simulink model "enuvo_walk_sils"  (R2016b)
settings: Solver=ode23tb  StartTime=0.0  StopTime=LAST_TIME  FixedStep=0.01  EnableMultiTasking=on
PreLoadFcn:
  | load('PID_PARAMETER');
  | N=40;
  | eta=1;
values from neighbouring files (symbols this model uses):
  A = [1 0 0 0 0 0    [symbolic_sample.m]
  s = robot_para.s    [kinematics_calc.m]    (also in plot_graph.m; robot_parameter.m = 40; robot_view.m)
undefined symbols (not defined in the file or in its folder): arm, bridge, constant, deg, kg, m, powergui, pulses, rad, S, Torque
libraries: mblibv1 x53, powerlib x7, powerlib_extras x1
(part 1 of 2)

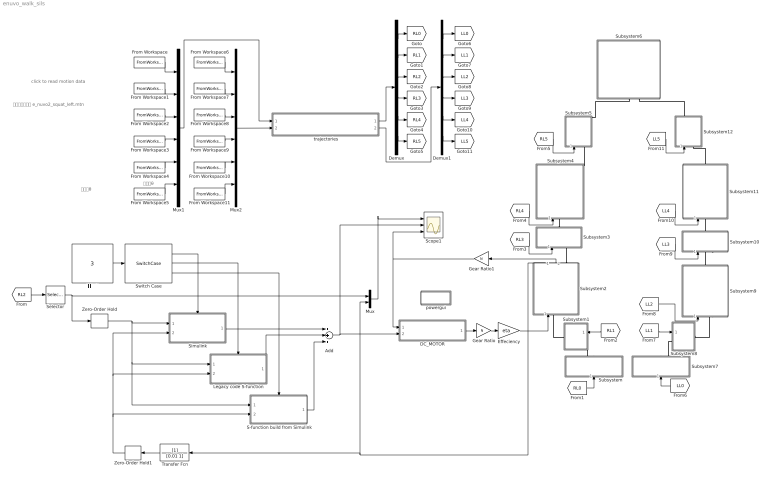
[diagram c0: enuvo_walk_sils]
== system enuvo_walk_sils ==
  note: click to read motion data
  note: 使用モーション e_nuvo2_squat_left.mtn
  note: 右足のθ
  note: 左足のθ
  Add : Sum  Inputs=+++
  DC_MOTOR : Subsystem
  Demux : Demux  Outputs=6
  Demux1 : Demux  Outputs=6
  Effeciency : Gain  Gain=eta
  From Workspace : FromWorkspace  VariableName=ID0_data  SampleTime=0
  From Workspace1 : FromWorkspace  VariableName=ID1_data  SampleTime=0
  From Workspace10 : FromWorkspace  VariableName=ID10_data  SampleTime=0
  From Workspace11 : FromWorkspace  VariableName=ID11_data  SampleTime=0
  From Workspace2 : FromWorkspace  VariableName=ID2_data  SampleTime=0
  From Workspace3 : FromWorkspace  VariableName=ID3_data  SampleTime=0
  From Workspace4 : FromWorkspace  VariableName=ID4_data  SampleTime=0
  From Workspace5 : FromWorkspace  VariableName=ID5_data  SampleTime=0
  From Workspace6 : FromWorkspace  VariableName=ID6_data  SampleTime=0
  From Workspace7 : FromWorkspace  VariableName=ID7_data  SampleTime=0
  From Workspace8 : FromWorkspace  VariableName=ID8_data  SampleTime=0
  From Workspace9 : FromWorkspace  VariableName=ID9_data  SampleTime=0
  Gear Ratio : Gain  Gain=N
  Gear Ratio1 : Gain  Gain=N
  Legacy code S-function : Subsystem  TreatAsAtomicUnit=on
  Mux : Mux  Inputs=2
  Mux1 : Mux  Inputs=6
  Mux2 : Mux  Inputs=6
  S-function build from Simulink : Subsystem  TreatAsAtomicUnit=on
  Scope1 : Scope  NumInputPorts=3
  Selector : Selector  InputPortWidth=3  IndexOptions=Index vector (dialog)  Indices=[1]  OutputSizes=1
  Simulink : Subsystem  TreatAsAtomicUnit=on
  Subsystem : Subsystem
  Subsystem1 : Subsystem
  Subsystem10 : Subsystem
  Subsystem11 : Subsystem
  Subsystem12 : Subsystem
  Subsystem2 : Subsystem
  Subsystem3 : Subsystem
  Subsystem4 : Subsystem
  Subsystem5 : Subsystem
  Subsystem6 : Subsystem
  Subsystem7 : Subsystem
  Subsystem8 : Subsystem
  Subsystem9 : Subsystem
  Switch Case : SwitchCase  CaseConditions={1,2,3}  ShowDefaultCase=off  SampleTime=20e-3
  Transfer Fcn : TransferFcn  Denominator=[0.01 1]
  Zero-Order Hold : ZeroOrderHold  SampleTime=20e-3
  Zero-Order Hold1 : ZeroOrderHold  SampleTime=20e-3
  powergui : Subsystem  AncestorBlock=powerlib/powergui  InitFcn=powergui( 'InitFcn_Callback' , gcb , 0 , [ ] );
  trajectories : Subsystem
  制御器切替 : Constant  Value=3
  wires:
  Gear Ratio/1 -> Effeciency/1
  DC_MOTOR/1(Te (n m)) -> Gear Ratio/1
  Selector/1 -> Mux/1, Zero-Order Hold/1
  Effeciency/1 -> Subsystem2/1(Torque(N m))
  Subsystem2/1(Theta(deg)) -> Mux/2, Transfer Fcn/1
  Mux/1 -> Scope1/1
  [RL2] -> Selector/1
  Subsystem2/2(w(rad/s)) -> Gear Ratio1/1
  Zero-Order Hold/1 -> Simulink/1(In1), Legacy code S-function/1(In1), S-function build from Simulink/1(In1)
  Zero-Order Hold1/1 -> Simulink/2(In2), Legacy code S-function/2(In2), S-function build from Simulink/2(In2)
  From Workspace/1 -> Mux1/1
  From Workspace1/1 -> Mux1/2
  From Workspace2/1 -> Mux1/3
  From Workspace3/1 -> Mux1/4
  From Workspace4/1 -> Mux1/5
  From Workspace5/1 -> Mux1/6
  From Workspace6/1 -> Mux2/1
  From Workspace7/1 -> Mux2/2
  From Workspace8/1 -> Mux2/3
  From Workspace9/1 -> Mux2/4
  From Workspace10/1 -> Mux2/5
  From Workspace11/1 -> Mux2/6
  Mux1/1 -> trajectories/1(θof RIGHT LEGS)
  Mux2/1 -> trajectories/2(θof LEFT LEGS)
  trajectories/1(θ,θ',θ''of RIGHT LEGS) -> Demux/1
  trajectories/2(θ,θ',θ''of LEFT LEGS) -> Demux1/1
  Demux/1 -> [RL0]
  Demux/2 -> [RL1]
  Demux/3 -> [RL2]
  Demux/4 -> [RL3]
  Demux/5 -> [RL4]
  Demux/6 -> [RL5]
  Demux1/1 -> [LL0]
  Demux1/2 -> [LL1]
  Demux1/3 -> [LL2]
  Demux1/4 -> [LL3]
  Demux1/5 -> [LL4]
  Demux1/6 -> [LL5]
  [RL0] -> Subsystem/1(motion)
  [RL1] -> Subsystem1/1(motion)
  [RL3] -> Subsystem3/1(motion)
  [RL4] -> Subsystem4/1(motion)
  [RL5] -> Subsystem5/1(motion)
  [LL0] -> Subsystem7/1(motion)
  [LL1] -> Subsystem8/1(motion)
  [LL2] -> Subsystem9/1(motion)
  [LL3] -> Subsystem10/1(motion)
  [LL4] -> Subsystem11/1(motion)
  [LL5] -> Subsystem12/1(motion)
  制御器切替/1 -> Switch Case/1
  Switch Case/1 -> Simulink/Action
  Switch Case/2 -> Legacy code S-function/Action
  Legacy code S-function/1(Out1) -> Add/2
  Switch Case/3 -> S-function build from Simulink/Action
  Simulink/1(Out1) -> Add/1
  S-function build from Simulink/1(Out1) -> Add/3
  Add/1 -> DC_MOTOR/2(Duty ratio[-]), Scope1/2
  Transfer Fcn/1 -> Zero-Order Hold1/1
  Gear Ratio1/1 -> DC_MOTOR/1(N w[rad/s]), Scope1/3
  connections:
  Subsystem1/LConn1 -- Subsystem/RConn1
  Subsystem2/LConn1 -- Subsystem1/RConn1
  Subsystem3/LConn1 -- Subsystem2/RConn1
  Subsystem6/LConn1 -- Subsystem5/RConn1
  Subsystem10/RConn1 -- Subsystem11/LConn1
  Subsystem9/RConn1 -- Subsystem10/LConn1
  Subsystem8/RConn1 -- Subsystem9/LConn1
  Subsystem8/LConn1 -- Subsystem7/RConn1
  Subsystem3/RConn1 -- Subsystem4/LConn1
  Subsystem4/RConn1 -- Subsystem5/LConn1
  Subsystem6/LConn2 -- Subsystem12/RConn1
  Subsystem12/LConn1 -- Subsystem11/RConn1

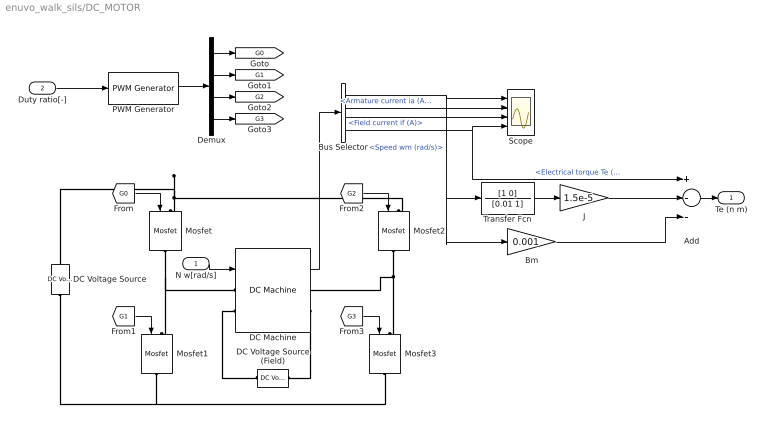
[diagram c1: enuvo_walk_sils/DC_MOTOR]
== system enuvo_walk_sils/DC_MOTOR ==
  N w[rad/s] : Inport
  Duty ratio[-] : Inport  Port=2
  Add : Sum  Inputs=+--
  Bm : Gain  Gain=0.001
  Bus Selector : BusSelector  OutputSignals=Speed wm (rad/s),Armature current ia (A),Field current if (A),Electrical torque Te (n m)
  DC Machine : powerlib/Machines/DC Machine  PresetModel=No  MechanicalLoad=Speed w  FieldType=Wound  ShowDetailedParameters=on  MeasurementBus=off  RLa="[ 10  4.4e-3]"  RLf="[ 24  0 ]"  Laf=0.05  MachineConstant=Torque constant (N.m/A)  Ke=1.8  Kt=1.8  J=1.5e-5  Bm=0.001  Tf=0  w0=0  Ifinit=1  TsPowergui=0  TsBlock=-1
  DC Voltage Source : powerlib/Electrical Sources/DC Voltage Source  Amplitude=24  Measurements=None
  DC Voltage Source (Field) : powerlib/Electrical Sources/DC Voltage Source  Amplitude=24  Measurements=None
  Demux : Demux
  J : Gain  Gain=1.5e-5
  Mosfet{,1..3} (4 alike) : powerlib/Power Electronics/Mosfet  Ron=0.3  Lon=0  Rd=0.01  Vfd=0  IC=0  Rs=5e9  Cs=inf  Measurements=off
  PWM Generator : powerlib_extras/Control  Blocks/PWM Generator  GeneratorMode="2-arm  bridge (4 pulses)"  Fc=500  Internal=off  mIndex=0.4  Freq=60  Phase=0
  Scope : Scope  NumInputPorts=4
  Transfer Fcn : TransferFcn  Numerator=[1 0]  Denominator=[0.01 1]
  Te (n m) : Outport
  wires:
  Duty ratio[-]/1 -> PWM Generator/1
  PWM Generator/1 -> Demux/1
  [G2] -> Mosfet2/1
  [G1] -> Mosfet1/1
  [G0] -> Mosfet/1
  Demux/4 -> [G3]
  Demux/3 -> [G2]
  Demux/2 -> [G1]
  Demux/1 -> [G0]
  Bus Selector/1 -> Scope/1, Bm/1, Transfer Fcn/1  "<Speed wm (rad/s)>"
  Bus Selector/2 -> Scope/2  "<Armature current ia (A)>"
  [G3] -> Mosfet3/1
  N w[rad/s]/1 -> DC Machine/1
  DC Machine/1 -> Bus Selector/1
  Bus Selector/3 -> Scope/3  "<Field current if (A)>"
  Bus Selector/4 -> Scope/4, Add/1  "<Electrical torque Te (n m)>"
  Bm/1 -> Add/3
  Transfer Fcn/1 -> J/1
  Add/1 -> Te (n m)/1
  J/1 -> Add/2
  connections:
  Mosfet2/RConn1 -- Mosfet3/LConn1 -- DC Machine/RConn1
  Mosfet/RConn1 -- Mosfet1/LConn1 -- DC Machine/LConn1
  Mosfet/LConn1 -- Mosfet2/LConn1 -- DC Voltage Source/RConn1
  Mosfet1/RConn1 -- Mosfet3/RConn1 -- DC Voltage Source/LConn1
  DC Voltage Source (Field)/RConn1 -- DC Machine/LConn2
  DC Machine/RConn2 -- DC Voltage Source (Field)/LConn1

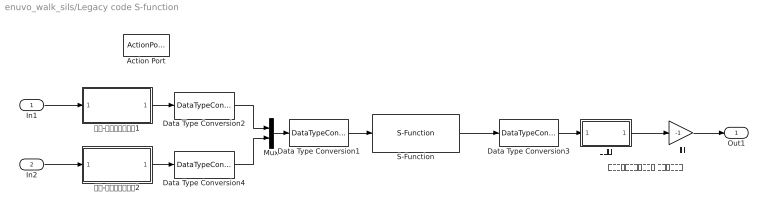
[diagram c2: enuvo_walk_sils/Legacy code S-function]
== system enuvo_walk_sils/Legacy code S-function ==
  note: レガシーコードの仕様と 合わせるため
  In1 : Inport
  In2 : Inport  Port=2
  Action Port : ActionPort  ActionType=case
  Data Type Conversion1 : DataTypeConversion  OutDataTypeStr=double
  Data Type Conversion2 : DataTypeConversion  OutDataTypeStr=uint16
  Data Type Conversion3 : DataTypeConversion  OutDataTypeStr=int16
  Data Type Conversion4 : DataTypeConversion  OutDataTypeStr=uint16
  Mux : Mux  Inputs=2
  S-Function : S-Function  FunctionName=sfun_pid  SFunctionDeploymentMode=off  EnableBusSupport=off
  正規化 : Subsystem
  符号反転 : Gain  Gain=-1
  角度-カウント値変換1 : Subsystem
  角度-カウント値変換2 : Subsystem
  Out1 : Outport
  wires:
  In2/1 -> 角度-カウント値変換2/1(theta[deg])
  符号反転/1 -> Out1/1
  Data Type Conversion4/1 -> Mux/2
  Data Type Conversion2/1 -> Mux/1
  角度-カウント値変換1/1(count[-]) -> Data Type Conversion2/1
  角度-カウント値変換2/1(count[-]) -> Data Type Conversion4/1
  S-Function/1 -> Data Type Conversion3/1
  正規化/1(Out1) -> 符号反転/1
  In1/1 -> 角度-カウント値変換1/1(theta[deg])
  Mux/1 -> Data Type Conversion1/1
  Data Type Conversion1/1 -> S-Function/1
  Data Type Conversion3/1 -> 正規化/1(In1)

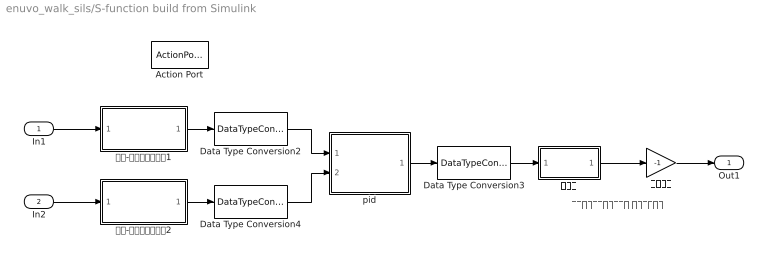
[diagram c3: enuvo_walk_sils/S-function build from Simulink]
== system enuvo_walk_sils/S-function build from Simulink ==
  note: レガシーコードの仕様と 合わせるため
  In1 : Inport
  In2 : Inport  Port=2
  Action Port : ActionPort  ActionType=case
  Data Type Conversion2 : DataTypeConversion  OutDataTypeStr=uint16
  Data Type Conversion3 : DataTypeConversion  OutDataTypeStr=int16
  Data Type Conversion4 : DataTypeConversion  OutDataTypeStr=uint16
  pid : Subsystem
  正規化 : Subsystem
  符号反転 : Gain  Gain=-1
  角度-カウント値変換1 : Subsystem
  角度-カウント値変換2 : Subsystem
  Out1 : Outport
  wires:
  Data Type Conversion3/1 -> 正規化/1(In1)
  In1/1 -> 角度-カウント値変換1/1(theta[deg])
  正規化/1(Out1) -> 符号反転/1
  pid/1(out) -> Data Type Conversion3/1
  角度-カウント値変換2/1(count[-]) -> Data Type Conversion4/1
  角度-カウント値変換1/1(count[-]) -> Data Type Conversion2/1
  符号反転/1 -> Out1/1
  In2/1 -> 角度-カウント値変換2/1(theta[deg])
  Data Type Conversion2/1 -> pid/1(ref)
  Data Type Conversion4/1 -> pid/2(pos)

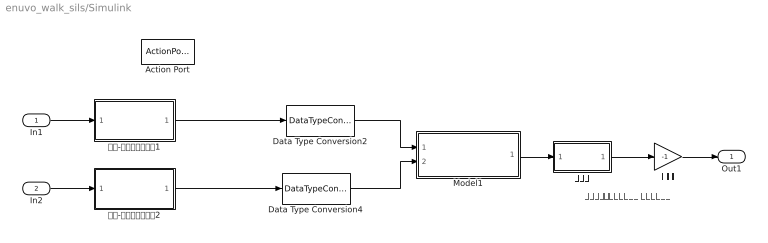
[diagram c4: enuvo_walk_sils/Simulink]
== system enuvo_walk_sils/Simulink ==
  note: レガシーコードの仕様と 合わせるため
  In1 : Inport
  In2 : Inport  Port=2
  Action Port : ActionPort  ActionType=case
  Data Type Conversion2 : DataTypeConversion  OutDataTypeStr=uint16
  Data Type Conversion4 : DataTypeConversion  OutDataTypeStr=uint16
  Model1 : ModelReference  ModelNameDialog=pid_body  ModelReferenceVersion=1.116
  正規化 : Subsystem
  符号反転 : Gain  Gain=-1
  角度-カウント値変換1 : Subsystem
  角度-カウント値変換2 : Subsystem
  Out1 : Outport
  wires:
  In1/1 -> 角度-カウント値変換1/1(theta[deg])
  正規化/1(Out1) -> 符号反転/1
  Model1/1 -> 正規化/1(In1)
  角度-カウント値変換2/1(count[-]) -> Data Type Conversion4/1
  角度-カウント値変換1/1(count[-]) -> Data Type Conversion2/1
  Data Type Conversion2/1 -> Model1/1
  Data Type Conversion4/1 -> Model1/2
  符号反転/1 -> Out1/1
  In2/1 -> 角度-カウント値変換2/1(theta[deg])

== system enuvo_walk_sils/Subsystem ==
  motion : Inport
  Body : mblibv1/Bodies/Body  LConnTagsString=CS1|CS3|CS4|CS5|CS6  RConnTagsString=CS2  UpdateFromCAD=off  DialogClass=MechanicalBodyBlock  Mass=8.7718241e-2  MassUnits=kg  InertiaUnits=kg*m^2  Inertia=1e-3*diag([4.5614162e-2 6.5533040e-2 5.6545514e-2])  Shape=Cylinder  ShapeDims=[1 1]  ShapeUnits=m  ShapeUse=false  Density=1  DensityUnits=kg/m^3  DensityUse=false  GraphicsMode=MACHINE_DEFAULT  BodyColorSelMode=MACHINE_DEFAULT  BodyColor=[1;0;0]  AttachedToCS=CG  CG=Left$CG$[7.96 -5.62 -13.41]$CS1$CS1$mm$[0 0 0]$Euler X-Y-Z$deg$WORLD$false  WorkingFrames=Left$CS1$[0 -20 40]$WORLD$WORLD$mm$[0 0 0]$Euler X-Y-Z$deg$WORLD$true#Right$CS2$[0 0 0]$CS1$CS1$mm$[0 0 0]$Euler X-Y-Z$deg$WORLD$true#Left$CS3$[65 12.5 -40]$CS1$CS1$mm$[0 0 0]$Euler X-Y-Z$deg$WORLD$true#Left$CS4$[-30 12.5 -40]$CS1$CS1$mm$[0 0 0]$Euler X-Y-Z$deg$WORLD$true#Left$CS5$[65 -42.5 -40]$CS1$CS1$mm$[0 0 0]$Euler X-Y-Z$deg$WORLD$true#Left$CS6$[-30 -42.5 -40]$CS1$CS1$mm$[0 0 0]$Euler X-Y-Z$d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  CGPos=[7.96 -5.62 -13.41]  CGRot=[0 0 0]  CS0Pos=[]  CS0Rot=[]  CS1Pos=[0 -20 40]  CS1Rot=[0 0 0]  CS2Pos=[0 0 0]  CS2Rot=[0 0 0]  CS3Pos=[65 12.5 -40]  CS3Rot=[0 0 0]  CS4Pos=[-30 12.5 -40]  CS4Rot=[0 0 0]  CS5Pos=[65 -42.5 -40]  CS5Rot=[0 0 0]  CS6Pos=[-30 -42.5 -40]  CS6Rot=[0 0 0]  CS7Pos=[]  CS7Rot=[]  CS8Pos=[]  CS8Rot=[]  CS9Pos=[]  CS9Rot=[]  CS10Pos=[]  CS10Rot=[]  CS11Pos=[]  CS11Rot=[]  CS12Pos=[]  CS12Rot=[]  CS13Pos=[]  CS13Rot=[]  CS14Pos=[]  CS14Rot=[]  CS15Pos=[]  CS15Rot=[]  CS16Pos=[]  CS16Rot=[]  CS17Pos=[]  CS17Rot=[]  CS18Pos=[]  CS18Rot=[]  CS19Pos=[]  CS19Rot=[]  CS20Pos=[]  CS20Rot=[]
  Joint Actuator : mblibv1/Sensors &  Actuators/Joint Actuator  UpdateFromCAD=off  PhysicalDomain=Mechanical  PortType=blob  ActuationStyle=Motion  AngleUnits=deg  ArcVelocityUnits=deg/s  ArcAccelerationUnits=deg/s^2  CoordPositionUnits=m  VelocityUnits=m/s  AccelerationUnits=m/s^2  ForceUnits=N  TorqueUnits=N-m  ActiveIO=on  Width=3  DialogClass=MechanicalActuatorBlock  Primitive=R1  ReferenceFrame=Absolute (INERTIAL)
  Mechanical Branching Bar : mblibv1/Utilities/Mechanical Branching Bar  LConnTagsString=_newl0  RConnTagsString=SA0|SA1  UpdateFromCAD=off  DialogClass=MechanicalBranchingBarBlock  NumSAPorts=2
  Revolute : mblibv1/Joints/Revolute  LConnTagsString=__newl0|SA1  RConnTagsString=__newr0  UpdateFromCAD=off  NumSAPorts=1  CutJoint=off  MarkAsCut=off  Primitives=revolute  PrimitiveProps=R1$WORLD$[-1 0 0]$revolute  DialogClass=JointBlock  R1Axis=[-1 0 0]
  Conn1 : PMIOPort  Port=1  Side=Right
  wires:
  motion/1 -> Joint Actuator/1
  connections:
  Conn1/RConn1 -- Revolute/RConn1
  Revolute/LConn1 -- Body/RConn1
  Mechanical Branching Bar/LConn1 -- Revolute/LConn2
  Joint Actuator/RConn1 -- Mechanical Branching Bar/RConn1

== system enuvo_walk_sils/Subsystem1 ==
  motion : Inport
  Body1 : mblibv1/Bodies/Body  LConnTagsString=CS1  RConnTagsString=CS2  UpdateFromCAD=off  DialogClass=MechanicalBodyBlock  Mass=1.7789708e-2  MassUnits=kg  InertiaUnits=kg*m^2  Inertia=1e-3*diag([3.2759472e-3 3.3173450e-3 4.8377597e-3])  Shape=Cylinder  ShapeDims=[1 1]  ShapeUnits=m  ShapeUse=false  Density=1  DensityUnits=kg/m^3  DensityUse=false  GraphicsMode=MACHINE_DEFAULT  BodyColorSelMode=MACHINE_DEFAULT  BodyColor=[1;0;0]  AttachedToCS=CG  CG=Left$CG$[-6.4 -13.1 0]$CS1$CS1$mm$[0 0 0]$Euler X-Y-Z$deg$WORLD$false  WorkingFrames=Left$CS1$[0 -20 40]$WORLD$WORLD$mm$[0 0 0]$Euler X-Y-Z$deg$WORLD$true#Right$CS2$[0 0 0]$CS1$CS1$mm$[0 0 0]$Euler X-Y-Z$deg$WORLD$true  CGPos=[-6.4 -13.1 0]  CGRot=[0 0 0]  CS0Pos=[]  CS0Rot=[]  CS1Pos=[0 -20 40]  CS1Rot=[0 0 0]  CS2Pos=[0 0 0]  CS2Rot=[0 0 0]  CS3Pos=[]  CS3Rot=[]  CS4Pos=[]  CS4Rot=[]  CS5Pos=[]  CS5Rot=[]  CS6Pos=[]  CS6Rot=[]  CS7Pos=[]  CS7Rot=[]  CS8Pos=[]  CS8Rot=[]  CS9Pos=[]  CS9Rot=[]  CS10Pos=[]  CS10Rot=[]  CS11Pos=[]  CS11Rot=[]  CS12Pos=[]  CS12Rot=[]  CS13Pos=[]  CS13Rot=[]  CS14Pos=[]  CS14Rot=[]  CS15Pos=[]  CS15Rot=[]  CS16Pos=[]  CS16Rot=[]  CS17Pos=[]  CS17Rot=[]  CS18Pos=[]  CS18Rot=[]  CS19Pos=[]  CS19Rot=[]  CS20Pos=[]  CS20Rot=[]
  Joint Actuator : mblibv1/Sensors &  Actuators/Joint Actuator  UpdateFromCAD=off  PhysicalDomain=Mechanical  PortType=blob  ActuationStyle=Motion  AngleUnits=deg  ArcVelocityUnits=deg/s  ArcAccelerationUnits=deg/s^2  CoordPositionUnits=m  VelocityUnits=m/s  AccelerationUnits=m/s^2  ForceUnits=N  TorqueUnits=N-m  ActiveIO=on  Width=3  DialogClass=MechanicalActuatorBlock  Primitive=R1  ReferenceFrame=Absolute (INERTIAL)
  Mechanical Branching Bar : mblibv1/Utilities/Mechanical Branching Bar  LConnTagsString=_newl0  RConnTagsString=SA0|SA1  UpdateFromCAD=off  DialogClass=MechanicalBranchingBarBlock  NumSAPorts=2
  Revolute1 : mblibv1/Joints/Revolute  LConnTagsString=__newl0|SA1  RConnTagsString=__newr0  UpdateFromCAD=off  NumSAPorts=1  CutJoint=off  MarkAsCut=off  Primitives=revolute  PrimitiveProps=R1$WORLD$[0 1 0]$revolute  DialogClass=JointBlock  R1Axis=[0 1 0]
  Conn1 : PMIOPort  Port=1  Side=Right
  Conn2 : PMIOPort  Port=2  Side=Left
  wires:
  motion/1 -> Joint Actuator/1
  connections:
  Body1/LConn1 -- Conn2/RConn1
  Revolute1/LConn1 -- Body1/RConn1
  Revolute1/RConn1 -- Conn1/RConn1
  Joint Actuator/RConn1 -- Mechanical Branching Bar/RConn1
  Mechanical Branching Bar/LConn1 -- Revolute1/LConn2

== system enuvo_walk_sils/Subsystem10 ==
  motion : Inport
  Body3 : mblibv1/Bodies/Body  LConnTagsString=CS2  RConnTagsString=CS1  UpdateFromCAD=off  DialogClass=MechanicalBodyBlock  Mass=1.9271167e-1  MassUnits=kg  InertiaUnits=kg*m^2  Inertia=1e-3*diag([2.6819268e-1 1.9711091e-1 1.0915260e-1])  Shape=Cylinder  ShapeDims=[1 1]  ShapeUnits=m  ShapeUse=false  Density=1  DensityUnits=kg/m^3  DensityUse=false  GraphicsMode=MACHINE_DEFAULT  BodyColorSelMode=MACHINE_DEFAULT  BodyColor=[1;0;0]  AttachedToCS=CG  CG=Left$CG$[7.6 30.24 -48.36]$CS1$CS1$mm$[0 0 0]$Euler X-Y-Z$deg$WORLD$false  WorkingFrames=Right$CS1$[0 20 210]$WORLD$WORLD$mm$[0 0 0]$Euler X-Y-Z$deg$WORLD$true#Left$CS2$[0 0 -85]$CS1$CS1$mm$[0 0 0]$Euler X-Y-Z$deg$WORLD$true  CGPos=[7.6 30.24 -48.36]  CGRot=[0 0 0]  CS0Pos=[]  CS0Rot=[]  CS1Pos=[0 20 210]  CS1Rot=[0 0 0]  CS2Pos=[0 0 -85]  CS2Rot=[0 0 0]  CS3Pos=[]  CS3Rot=[]  CS4Pos=[]  CS4Rot=[]  CS5Pos=[]  CS5Rot=[]  CS6Pos=[]  CS6Rot=[]  CS7Pos=[]  CS7Rot=[]  CS8Pos=[]  CS8Rot=[]  CS9Pos=[]  CS9Rot=[]  CS10Pos=[]  CS10Rot=[]  CS11Pos=[]  CS11Rot=[]  CS12Pos=[]  CS12Rot=[]  CS13Pos=[]  CS13Rot=[]  CS14Pos=[]  CS14Rot=[]  CS15Pos=[]  CS15Rot=[]  CS16Pos=[]  CS16Rot=[]  CS17Pos=[]  CS17Rot=[]  CS18Pos=[]  CS18Rot=[]  CS19Pos=[]  CS19Rot=[]  CS20Pos=[]  CS20Rot=[]
  Joint Actuator : mblibv1/Sensors &  Actuators/Joint Actuator  UpdateFromCAD=off  PhysicalDomain=Mechanical  PortType=blob  ActuationStyle=Motion  AngleUnits=deg  ArcVelocityUnits=deg/s  ArcAccelerationUnits=deg/s^2  CoordPositionUnits=m  VelocityUnits=m/s  AccelerationUnits=m/s^2  ForceUnits=N  TorqueUnits=N-m  ActiveIO=on  Width=3  DialogClass=MechanicalActuatorBlock  Primitive=R1  ReferenceFrame=Absolute (INERTIAL)
  Mechanical Branching Bar : mblibv1/Utilities/Mechanical Branching Bar  LConnTagsString=_newl0  RConnTagsString=SA0|SA1  UpdateFromCAD=off  DialogClass=MechanicalBranchingBarBlock  NumSAPorts=2
  Revolute3 : mblibv1/Joints/Revolute  LConnTagsString=__newl0|SA1  RConnTagsString=__newr0  UpdateFromCAD=off  NumSAPorts=1  CutJoint=off  MarkAsCut=off  Primitives=revolute  PrimitiveProps=R1$WORLD$[0 -1 0]$revolute  DialogClass=JointBlock  R1Axis=[0 -1 0]
  Conn1 : PMIOPort  Port=1  Side=Right
  Conn2 : PMIOPort  Port=2  Side=Left
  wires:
  motion/1 -> Joint Actuator/1
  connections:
  Body3/LConn1 -- Conn2/RConn1
  Body3/RConn1 -- Revolute3/LConn1
  Revolute3/RConn1 -- Conn1/RConn1
  Joint Actuator/RConn1 -- Mechanical Branching Bar/RConn1
  Mechanical Branching Bar/LConn1 -- Revolute3/LConn2

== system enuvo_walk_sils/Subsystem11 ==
  motion : Inport
  Body4 : mblibv1/Bodies/Body  LConnTagsString=CS1  RConnTagsString=CS2  UpdateFromCAD=off  DialogClass=MechanicalBodyBlock  Mass=1.9496011e-2  MassUnits=kg  InertiaUnits=kg*m^2  Inertia=1e-3*diag([3.4019114e-3 6.0240860e-3 7.5327744e-3])  Shape=Cylinder  ShapeDims=[1 1]  ShapeUnits=m  ShapeUse=false  Density=1  DensityUnits=kg/m^3  DensityUse=false  GraphicsMode=MACHINE_DEFAULT  BodyColorSelMode=MACHINE_DEFAULT  BodyColor=[1;0;0]  AttachedToCS=CG  CG=Left$CG$[22.94 16.61 0]$CS1$CS1$mm$[0 0 0]$Euler X-Y-Z$deg$WORLD$false  WorkingFrames=Left$CS1$[0 20 210]$WORLD$WORLD$mm$[0 0 0]$Euler X-Y-Z$deg$WORLD$true#Right$CS2$[0 0 0]$CS1$CS1$mm$[0 0 0]$Euler X-Y-Z$deg$WORLD$true  CGPos=[22.94 16.61 0]  CGRot=[0 0 0]  CS0Pos=[]  CS0Rot=[]  CS1Pos=[0 20 210]  CS1Rot=[0 0 0]  CS2Pos=[0 0 0]  CS2Rot=[0 0 0]  CS3Pos=[]  CS3Rot=[]  CS4Pos=[]  CS4Rot=[]  CS5Pos=[]  CS5Rot=[]  CS6Pos=[]  CS6Rot=[]  CS7Pos=[]  CS7Rot=[]  CS8Pos=[]  CS8Rot=[]  CS9Pos=[]  CS9Rot=[]  CS10Pos=[]  CS10Rot=[]  CS11Pos=[]  CS11Rot=[]  CS12Pos=[]  CS12Rot=[]  CS13Pos=[]  CS13Rot=[]  CS14Pos=[]  CS14Rot=[]  CS15Pos=[]  CS15Rot=[]  CS16Pos=[]  CS16Rot=[]  CS17Pos=[]  CS17Rot=[]  CS18Pos=[]  CS18Rot=[]  CS19Pos=[]  CS19Rot=[]  CS20Pos=[]  CS20Rot=[]
  Joint Actuator : mblibv1/Sensors &  Actuators/Joint Actuator  UpdateFromCAD=off  PhysicalDomain=Mechanical  PortType=blob  ActuationStyle=Motion  AngleUnits=deg  ArcVelocityUnits=deg/s  ArcAccelerationUnits=deg/s^2  CoordPositionUnits=m  VelocityUnits=m/s  AccelerationUnits=m/s^2  ForceUnits=N  TorqueUnits=N-m  ActiveIO=on  Width=3  DialogClass=MechanicalActuatorBlock  Primitive=R1  ReferenceFrame=Absolute (INERTIAL)
  Mechanical Branching Bar : mblibv1/Utilities/Mechanical Branching Bar  LConnTagsString=_newl0  RConnTagsString=SA0|SA1  UpdateFromCAD=off  DialogClass=MechanicalBranchingBarBlock  NumSAPorts=2
  Revolute4 : mblibv1/Joints/Revolute  LConnTagsString=__newl0|SA1  RConnTagsString=__newr0  UpdateFromCAD=off  NumSAPorts=1  CutJoint=off  MarkAsCut=off  Primitives=revolute  PrimitiveProps=R1$WORLD$[1 0 0]$revolute  DialogClass=JointBlock  R1Axis=[1 0 0]
  Conn1 : PMIOPort  Port=1  Side=Left
  Conn2 : PMIOPort  Port=2  Side=Right
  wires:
  motion/1 -> Joint Actuator/1
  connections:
  Conn1/RConn1 -- Body4/RConn1
  Revolute4/LConn1 -- Body4/LConn1
  Revolute4/RConn1 -- Conn2/RConn1
  Mechanical Branching Bar/RConn1 -- Joint Actuator/RConn1
  Mechanical Branching Bar/LConn1 -- Revolute4/LConn2

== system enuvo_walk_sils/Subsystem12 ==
  motion : Inport
  Body5 : mblibv1/Bodies/Body  LConnTagsString=CS1  RConnTagsString=CS2  UpdateFromCAD=off  DialogClass=MechanicalBodyBlock  Mass=6.8553842e-2  MassUnits=kg  InertiaUnits=kg*m^2  Inertia=1e-3*diag([9.4722975e-3 2.4214009e-2 1.8460665e-2])  Shape=Cylinder  ShapeDims=[1 1]  ShapeUnits=m  ShapeUse=false  Density=1  DensityUnits=kg/m^3  DensityUse=false  GraphicsMode=MACHINE_DEFAULT  BodyColorSelMode=MACHINE_DEFAULT  BodyColor=[1;0;0]  AttachedToCS=CG  CG=Left$CG$[7.11 0 5.09]$CS1$CS1$mm$[0 0 0]$Euler X-Y-Z$deg$WORLD$false  WorkingFrames=Left$CS1$[0 20 210]$WORLD$WORLD$mm$[0 0 0]$Euler X-Y-Z$deg$WORLD$true#Right$CS2$[0 0 0]$CS1$CS1$mm$[0 0 0]$Euler X-Y-Z$deg$WORLD$true  CGPos=[7.11 0 5.09]  CGRot=[0 0 0]  CS0Pos=[]  CS0Rot=[]  CS1Pos=[0 20 210]  CS1Rot=[0 0 0]  CS2Pos=[0 0 0]  CS2Rot=[0 0 0]  CS3Pos=[]  CS3Rot=[]  CS4Pos=[]  CS4Rot=[]  CS5Pos=[]  CS5Rot=[]  CS6Pos=[]  CS6Rot=[]  CS7Pos=[]  CS7Rot=[]  CS8Pos=[]  CS8Rot=[]  CS9Pos=[]  CS9Rot=[]  CS10Pos=[]  CS10Rot=[]  CS11Pos=[]  CS11Rot=[]  CS12Pos=[]  CS12Rot=[]  CS13Pos=[]  CS13Rot=[]  CS14Pos=[]  CS14Rot=[]  CS15Pos=[]  CS15Rot=[]  CS16Pos=[]  CS16Rot=[]  CS17Pos=[]  CS17Rot=[]  CS18Pos=[]  CS18Rot=[]  CS19Pos=[]  CS19Rot=[]  CS20Pos=[]  CS20Rot=[]
  Joint Actuator : mblibv1/Sensors &  Actuators/Joint Actuator  UpdateFromCAD=off  PhysicalDomain=Mechanical  PortType=blob  ActuationStyle=Motion  AngleUnits=deg  ArcVelocityUnits=deg/s  ArcAccelerationUnits=deg/s^2  CoordPositionUnits=m  VelocityUnits=m/s  AccelerationUnits=m/s^2  ForceUnits=N  TorqueUnits=N-m  ActiveIO=on  Width=3  DialogClass=MechanicalActuatorBlock  Primitive=R1  ReferenceFrame=Absolute (INERTIAL)
  Mechanical Branching Bar : mblibv1/Utilities/Mechanical Branching Bar  LConnTagsString=_newl0  RConnTagsString=SA0|SA1  UpdateFromCAD=off  DialogClass=MechanicalBranchingBarBlock  NumSAPorts=2
  Revolute5 : mblibv1/Joints/Revolute  LConnTagsString=__newl0|SA1  RConnTagsString=__newr0  UpdateFromCAD=off  NumSAPorts=1  CutJoint=off  MarkAsCut=off  Primitives=revolute  PrimitiveProps=R1$WORLD$[0 0 1]$revolute  DialogClass=JointBlock  R1Axis=[0 0 1]
  Conn1 : PMIOPort  Port=1  Side=Right
  Conn2 : PMIOPort  Port=2  Side=Left
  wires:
  motion/1 -> Joint Actuator/1
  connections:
  Conn2/RConn1 -- Body5/LConn1
  Revolute5/LConn1 -- Body5/RConn1
  Revolute5/RConn1 -- Conn1/RConn1
  Mechanical Branching Bar/RConn1 -- Joint Actuator/RConn1
  Mechanical Branching Bar/LConn1 -- Revolute5/LConn2

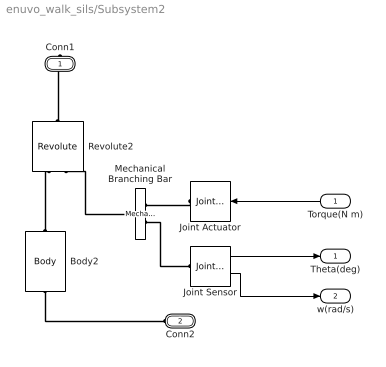
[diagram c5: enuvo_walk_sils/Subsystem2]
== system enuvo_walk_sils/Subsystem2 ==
  Torque(N m) : Inport
  Body2 : mblibv1/Bodies/Body  LConnTagsString=CS1  RConnTagsString=CS2  UpdateFromCAD=off  DialogClass=MechanicalBodyBlock  Mass=1.2799082e-1  MassUnits=kg  InertiaUnits=kg*m^2  Inertia=1e-3*diag([1.2927724e-1 9.7937726e-2 5.7245228e-2])  Shape=Cylinder  ShapeDims=[1 1]  ShapeUnits=m  ShapeUse=false  Density=1  DensityUnits=kg/m^3  DensityUse=false  GraphicsMode=MACHINE_DEFAULT  BodyColorSelMode=MACHINE_DEFAULT  BodyColor=[1;0;0]  AttachedToCS=CG  CG=Left$CG$[10.55 -32.59 38.17]$CS1$CS1$mm$[0 0 0]$Euler X-Y-Z$deg$WORLD$false  WorkingFrames=Left$CS1$[0 -20 40]$WORLD$WORLD$mm$[0 0 0]$Euler X-Y-Z$deg$WORLD$true#Right$CS2$[0 0 85]$CS1$CS1$mm$[0 0 0]$Euler X-Y-Z$deg$WORLD$true  CGPos=[10.55 -32.59 38.17]  CGRot=[0 0 0]  CS0Pos=[]  CS0Rot=[]  CS1Pos=[0 -20 40]  CS1Rot=[0 0 0]  CS2Pos=[0 0 85]  CS2Rot=[0 0 0]  CS3Pos=[]  CS3Rot=[]  CS4Pos=[]  CS4Rot=[]  CS5Pos=[]  CS5Rot=[]  CS6Pos=[]  CS6Rot=[]  CS7Pos=[]  CS7Rot=[]  CS8Pos=[]  CS8Rot=[]  CS9Pos=[]  CS9Rot=[]  CS10Pos=[]  CS10Rot=[]  CS11Pos=[]  CS11Rot=[]  CS12Pos=[]  CS12Rot=[]  CS13Pos=[]  CS13Rot=[]  CS14Pos=[]  CS14Rot=[]  CS15Pos=[]  CS15Rot=[]  CS16Pos=[]  CS16Rot=[]  CS17Pos=[]  CS17Rot=[]  CS18Pos=[]  CS18Rot=[]  CS19Pos=[]  CS19Rot=[]  CS20Pos=[]  CS20Rot=[]
  Joint Actuator : mblibv1/Sensors &  Actuators/Joint Actuator  UpdateFromCAD=off  PhysicalDomain=Mechanical  PortType=blob  ActuationStyle=Force  AngleUnits=deg  ArcVelocityUnits=deg/s  ArcAccelerationUnits=deg/s^2  CoordPositionUnits=m  VelocityUnits=m/s  AccelerationUnits=m/s^2  ForceUnits=N  TorqueUnits=N-m  ActiveIO=on  Width=1  DialogClass=MechanicalActuatorBlock  Primitive=R1  ReferenceFrame=Absolute (INERTIAL)
  Joint Sensor : mblibv1/Sensors &  Actuators/Joint Sensor  UpdateFromCAD=off  PhysicalDomain=Mechanical  PortType=blob  Muxed=off  Pose=off  Angle=on  AngleUnits=deg  ArcVelocity=on  ArcVelocityUnits=rad/s  ArcAcceleration=off  ArcAccelerationUnits=deg/s^2  CoordPosition=on  CoordPositionUnits=m  Velocity=off  VelocityUnits=m/s  Acceleration=off  AccelerationUnits=m/s^2  Quaternion=on  QuaternionDT=off  QuaternionDDT=off  QuaternionUnits=off  OutputVector=[ 1 1 ]  ActiveIO=on  Width=2  DialogClass=MechanicalSensorBlock  Primitive=R1  Force=off  ForceUnits=N  Torque=off  TorqueUnits=N-m  ReferenceFrame=Absolute (INERTIAL)  ReactionSensedSide=Base  ReactionReferenceFrame=Local (Body CS)  ReactionForce=off  ReactionForceUnits=N  ReactionMoment=off  ReactionMomentUnits=N-m
  Mechanical Branching Bar : mblibv1/Utilities/Mechanical Branching Bar  LConnTagsString=_newl0  RConnTagsString=SA0|SA1  UpdateFromCAD=off  DialogClass=MechanicalBranchingBarBlock  NumSAPorts=2
  Revolute2 : mblibv1/Joints/Revolute  LConnTagsString=__newl0|SA1  RConnTagsString=__newr0  UpdateFromCAD=off  NumSAPorts=1  CutJoint=off  MarkAsCut=off  Primitives=revolute  PrimitiveProps=R1$WORLD$[0 1 0]$revolute  DialogClass=JointBlock  R1Axis=[0 1 0]
  Conn1 : PMIOPort  Port=1  Side=Right
  Conn2 : PMIOPort  Port=2  Side=Left
  Theta(deg) : Outport
  w(rad/s) : Outport  Port=2
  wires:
  Joint Sensor/1 -> Theta(deg)/1
  Torque(N m)/1 -> Joint Actuator/1
  Joint Sensor/2 -> w(rad/s)/1
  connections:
  Body2/LConn1 -- Conn2/RConn1
  Body2/RConn1 -- Revolute2/LConn1
  Revolute2/RConn1 -- Conn1/RConn1
  Joint Actuator/RConn1 -- Mechanical Branching Bar/RConn1
  Mechanical Branching Bar/LConn1 -- Revolute2/LConn2
  Mechanical Branching Bar/RConn2 -- Joint Sensor/LConn1

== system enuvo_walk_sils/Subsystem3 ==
  motion : Inport
  Body3 : mblibv1/Bodies/Body  LConnTagsString=CS2  RConnTagsString=CS1  UpdateFromCAD=off  DialogClass=MechanicalBodyBlock  Mass=1.9271167e-1  MassUnits=kg  InertiaUnits=kg*m^2  Inertia=1e-3*diag([2.6819268e-1 1.9711091e-1 1.0915260e-1])  Shape=Cylinder  ShapeDims=[1 1]  ShapeUnits=m  ShapeUse=false  Density=1  DensityUnits=kg/m^3  DensityUse=false  GraphicsMode=MACHINE_DEFAULT  BodyColorSelMode=MACHINE_DEFAULT  BodyColor=[1;0;0]  AttachedToCS=CG  CG=Left$CG$[7.6 -30.24 -48.36]$CS1$CS1$mm$[0 0 0]$Euler X-Y-Z$deg$WORLD$false  WorkingFrames=Right$CS1$[0 -20 210]$WORLD$WORLD$mm$[0 0 0]$Euler X-Y-Z$deg$WORLD$true#Left$CS2$[0 0 -85]$CS1$CS1$mm$[0 0 0]$Euler X-Y-Z$deg$WORLD$true  CGPos=[7.6 -30.24 -48.36]  CGRot=[0 0 0]  CS0Pos=[]  CS0Rot=[]  CS1Pos=[0 -20 210]  CS1Rot=[0 0 0]  CS2Pos=[0 0 -85]  CS2Rot=[0 0 0]  CS3Pos=[]  CS3Rot=[]  CS4Pos=[]  CS4Rot=[]  CS5Pos=[]  CS5Rot=[]  CS6Pos=[]  CS6Rot=[]  CS7Pos=[]  CS7Rot=[]  CS8Pos=[]  CS8Rot=[]  CS9Pos=[]  CS9Rot=[]  CS10Pos=[]  CS10Rot=[]  CS11Pos=[]  CS11Rot=[]  CS12Pos=[]  CS12Rot=[]  CS13Pos=[]  CS13Rot=[]  CS14Pos=[]  CS14Rot=[]  CS15Pos=[]  CS15Rot=[]  CS16Pos=[]  CS16Rot=[]  CS17Pos=[]  CS17Rot=[]  CS18Pos=[]  CS18Rot=[]  CS19Pos=[]  CS19Rot=[]  CS20Pos=[]  CS20Rot=[]
  Joint Actuator : mblibv1/Sensors &  Actuators/Joint Actuator  UpdateFromCAD=off  PhysicalDomain=Mechanical  PortType=blob  ActuationStyle=Motion  AngleUnits=deg  ArcVelocityUnits=deg/s  ArcAccelerationUnits=deg/s^2  CoordPositionUnits=m  VelocityUnits=m/s  AccelerationUnits=m/s^2  ForceUnits=N  TorqueUnits=N-m  ActiveIO=on  Width=3  DialogClass=MechanicalActuatorBlock  Primitive=R1  ReferenceFrame=Absolute (INERTIAL)
  Mechanical Branching Bar : mblibv1/Utilities/Mechanical Branching Bar  LConnTagsString=_newl0  RConnTagsString=SA0|SA1  UpdateFromCAD=off  DialogClass=MechanicalBranchingBarBlock  NumSAPorts=2
  Revolute3 : mblibv1/Joints/Revolute  LConnTagsString=__newl0|SA1  RConnTagsString=__newr0  UpdateFromCAD=off  NumSAPorts=1  CutJoint=off  MarkAsCut=off  Primitives=revolute  PrimitiveProps=R1$WORLD$[0 -1 0]$revolute  DialogClass=JointBlock  R1Axis=[0 -1 0]
  Conn1 : PMIOPort  Port=1  Side=Right
  Conn2 : PMIOPort  Port=2  Side=Left
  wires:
  motion/1 -> Joint Actuator/1
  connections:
  Body3/LConn1 -- Conn2/RConn1
  Body3/RConn1 -- Revolute3/LConn1
  Revolute3/RConn1 -- Conn1/RConn1
  Joint Actuator/RConn1 -- Mechanical Branching Bar/RConn1
  Mechanical Branching Bar/LConn1 -- Revolute3/LConn2

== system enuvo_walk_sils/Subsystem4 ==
  motion : Inport
  Body4 : mblibv1/Bodies/Body  LConnTagsString=CS1  RConnTagsString=CS2  UpdateFromCAD=off  DialogClass=MechanicalBodyBlock  Mass=1.9496011e-2  MassUnits=kg  InertiaUnits=kg*m^2  Inertia=1e-3*diag([3.4019114e-3 6.0240860e-3 7.5327744e-3])  Shape=Cylinder  ShapeDims=[1 1]  ShapeUnits=m  ShapeUse=false  Density=1  DensityUnits=kg/m^3  DensityUse=false  GraphicsMode=MACHINE_DEFAULT  BodyColorSelMode=MACHINE_DEFAULT  BodyColor=[1;0;0]  AttachedToCS=CG  CG=Left$CG$[22.94 -16.61 0]$CS1$CS1$mm$[0 0 0]$Euler X-Y-Z$deg$WORLD$false  WorkingFrames=Left$CS1$[0 -20 210]$WORLD$WORLD$mm$[0 0 0]$Euler X-Y-Z$deg$WORLD$true#Right$CS2$[0 0 0]$CS1$CS1$mm$[0 0 0]$Euler X-Y-Z$deg$WORLD$true  CGPos=[22.94 -16.61 0]  CGRot=[0 0 0]  CS0Pos=[]  CS0Rot=[]  CS1Pos=[0 -20 210]  CS1Rot=[0 0 0]  CS2Pos=[0 0 0]  CS2Rot=[0 0 0]  CS3Pos=[]  CS3Rot=[]  CS4Pos=[]  CS4Rot=[]  CS5Pos=[]  CS5Rot=[]  CS6Pos=[]  CS6Rot=[]  CS7Pos=[]  CS7Rot=[]  CS8Pos=[]  CS8Rot=[]  CS9Pos=[]  CS9Rot=[]  CS10Pos=[]  CS10Rot=[]  CS11Pos=[]  CS11Rot=[]  CS12Pos=[]  CS12Rot=[]  CS13Pos=[]  CS13Rot=[]  CS14Pos=[]  CS14Rot=[]  CS15Pos=[]  CS15Rot=[]  CS16Pos=[]  CS16Rot=[]  CS17Pos=[]  CS17Rot=[]  CS18Pos=[]  CS18Rot=[]  CS19Pos=[]  CS19Rot=[]  CS20Pos=[]  CS20Rot=[]
  Joint Actuator : mblibv1/Sensors &  Actuators/Joint Actuator  UpdateFromCAD=off  PhysicalDomain=Mechanical  PortType=blob  ActuationStyle=Motion  AngleUnits=deg  ArcVelocityUnits=deg/s  ArcAccelerationUnits=deg/s^2  CoordPositionUnits=m  VelocityUnits=m/s  AccelerationUnits=m/s^2  ForceUnits=N  TorqueUnits=N-m  ActiveIO=on  Width=3  DialogClass=MechanicalActuatorBlock  Primitive=R1  ReferenceFrame=Absolute (INERTIAL)
  Mechanical Branching Bar : mblibv1/Utilities/Mechanical Branching Bar  LConnTagsString=_newl0  RConnTagsString=SA0|SA1  UpdateFromCAD=off  DialogClass=MechanicalBranchingBarBlock  NumSAPorts=2
  Revolute4 : mblibv1/Joints/Revolute  LConnTagsString=__newl0|SA1  RConnTagsString=__newr0  UpdateFromCAD=off  NumSAPorts=1  CutJoint=off  MarkAsCut=off  Primitives=revolute  PrimitiveProps=R1$WORLD$[-1 0 0]$revolute  DialogClass=JointBlock  R1Axis=[-1 0 0]
  Conn1 : PMIOPort  Port=1  Side=Left
  Conn2 : PMIOPort  Port=2  Side=Right
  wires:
  motion/1 -> Joint Actuator/1
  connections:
  Conn1/RConn1 -- Body4/RConn1
  Revolute4/LConn1 -- Body4/LConn1
  Revolute4/RConn1 -- Conn2/RConn1
  Mechanical Branching Bar/RConn1 -- Joint Actuator/RConn1
  Mechanical Branching Bar/LConn1 -- Revolute4/LConn2

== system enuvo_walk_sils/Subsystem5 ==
  motion : Inport
  Body5 : mblibv1/Bodies/Body  LConnTagsString=CS1  RConnTagsString=CS2  UpdateFromCAD=off  DialogClass=MechanicalBodyBlock  Mass=6.8553842e-2  MassUnits=kg  InertiaUnits=kg*m^2  Inertia=1e-3*diag([9.4722975e-3 2.4214009e-2 1.8460665e-2])  Shape=Cylinder  ShapeDims=[1 1]  ShapeUnits=m  ShapeUse=false  Density=1  DensityUnits=kg/m^3  DensityUse=false  GraphicsMode=MACHINE_DEFAULT  BodyColorSelMode=MACHINE_DEFAULT  BodyColor=[1;0;0]  AttachedToCS=CG  CG=Left$CG$[7.11 0 5.09]$CS1$CS1$mm$[0 0 0]$Euler X-Y-Z$deg$WORLD$false  WorkingFrames=Left$CS1$[0 -20 210]$WORLD$WORLD$mm$[0 0 0]$Euler X-Y-Z$deg$WORLD$true#Right$CS2$[0 0 0]$CS1$CS1$mm$[0 0 0]$Euler X-Y-Z$deg$WORLD$true  CGPos=[7.11 0 5.09]  CGRot=[0 0 0]  CS0Pos=[]  CS0Rot=[]  CS1Pos=[0 -20 210]  CS1Rot=[0 0 0]  CS2Pos=[0 0 0]  CS2Rot=[0 0 0]  CS3Pos=[]  CS3Rot=[]  CS4Pos=[]  CS4Rot=[]  CS5Pos=[]  CS5Rot=[]  CS6Pos=[]  CS6Rot=[]  CS7Pos=[]  CS7Rot=[]  CS8Pos=[]  CS8Rot=[]  CS9Pos=[]  CS9Rot=[]  CS10Pos=[]  CS10Rot=[]  CS11Pos=[]  CS11Rot=[]  CS12Pos=[]  CS12Rot=[]  CS13Pos=[]  CS13Rot=[]  CS14Pos=[]  CS14Rot=[]  CS15Pos=[]  CS15Rot=[]  CS16Pos=[]  CS16Rot=[]  CS17Pos=[]  CS17Rot=[]  CS18Pos=[]  CS18Rot=[]  CS19Pos=[]  CS19Rot=[]  CS20Pos=[]  CS20Rot=[]
  Joint Actuator : mblibv1/Sensors &  Actuators/Joint Actuator  UpdateFromCAD=off  PhysicalDomain=Mechanical  PortType=blob  ActuationStyle=Motion  AngleUnits=deg  ArcVelocityUnits=deg/s  ArcAccelerationUnits=deg/s^2  CoordPositionUnits=m  VelocityUnits=m/s  AccelerationUnits=m/s^2  ForceUnits=N  TorqueUnits=N-m  ActiveIO=on  Width=3  DialogClass=MechanicalActuatorBlock  Primitive=R1  ReferenceFrame=Absolute (INERTIAL)
  Mechanical Branching Bar : mblibv1/Utilities/Mechanical Branching Bar  LConnTagsString=_newl0  RConnTagsString=SA0|SA1  UpdateFromCAD=off  DialogClass=MechanicalBranchingBarBlock  NumSAPorts=2
  Revolute5 : mblibv1/Joints/Revolute  LConnTagsString=__newl0|SA1  RConnTagsString=__newr0  UpdateFromCAD=off  NumSAPorts=1  CutJoint=off  MarkAsCut=off  Primitives=revolute  PrimitiveProps=R1$WORLD$[0 0 -1]$revolute  DialogClass=JointBlock  R1Axis=[0 0 -1]
  Conn1 : PMIOPort  Port=1  Side=Right
  Conn2 : PMIOPort  Port=2  Side=Left
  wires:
  motion/1 -> Joint Actuator/1
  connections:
  Conn2/RConn1 -- Body5/LConn1
  Revolute5/LConn1 -- Body5/RConn1
  Revolute5/RConn1 -- Conn1/RConn1
  Mechanical Branching Bar/RConn1 -- Joint Actuator/RConn1
  Mechanical Branching Bar/LConn1 -- Revolute5/LConn2

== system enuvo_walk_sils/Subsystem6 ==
  Body6 : mblibv1/Bodies/Body  LConnTagsString=CS2  RConnTagsString=CS3  UpdateFromCAD=off  DialogClass=MechanicalBodyBlock  Mass=3.7169733e-1  MassUnits=kg  InertiaUnits=kg*m^2  Inertia=1e-3*diag([2.9758908e-1 3.0497682e-1 2.7400693e-1])  Shape=Cylinder  ShapeDims=[1 1]  ShapeUnits=m  ShapeUse=false  Density=1  DensityUnits=kg/m^3  DensityUse=false  GraphicsMode=MACHINE_DEFAULT  BodyColorSelMode=MACHINE_DEFAULT  BodyColor=[1;0;0]  AttachedToCS=CG  CG=Left$CG$[0 0 31.68]$CS1$CS1$mm$[0 0 0]$Euler X-Y-Z$deg$WORLD$false  WorkingFrames=Left$CS1$[0 0 244]$WORLD$WORLD$mm$[0 0 0]$Euler X-Y-Z$deg$WORLD$false#Left$CS2$[0 -20 -34]$CS1$CS1$mm$[0 0 0]$Euler X-Y-Z$deg$WORLD$true#Right$CS3$[0 20 -34]$CS1$CS1$mm$[0 0 0]$Euler X-Y-Z$deg$WORLD$true  CGPos=[0 0 31.68]  CGRot=[0 0 0]  CS0Pos=[]  CS0Rot=[]  CS1Pos=[0 0 244]  CS1Rot=[0 0 0]  CS2Pos=[0 -20 -34]  CS2Rot=[0 0 0]  CS3Pos=[0 20 -34]  CS3Rot=[0 0 0]  CS4Pos=[]  CS4Rot=[]  CS5Pos=[]  CS5Rot=[]  CS6Pos=[]  CS6Rot=[]  CS7Pos=[]  CS7Rot=[]  CS8Pos=[]  CS8Rot=[]  CS9Pos=[]  CS9Rot=[]  CS10Pos=[]  CS10Rot=[]  CS11Pos=[]  CS11Rot=[]  CS12Pos=[]  CS12Rot=[]  CS13Pos=[]  CS13Rot=[]  CS14Pos=[]  CS14Rot=[]  CS15Pos=[]  CS15Rot=[]  CS16Pos=[]  CS16Rot=[]  CS17Pos=[]  CS17Rot=[]  CS18Pos=[]  CS18Rot=[]  CS19Pos=[]  CS19Rot=[]  CS20Pos=[]  CS20Rot=[]
  Conn2 : PMIOPort  Port=1  Side=Left
  Conn1 : PMIOPort  Port=2  Side=Left
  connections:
  Body6/LConn1 -- Conn2/RConn1
  Body6/RConn1 -- Conn1/RConn1

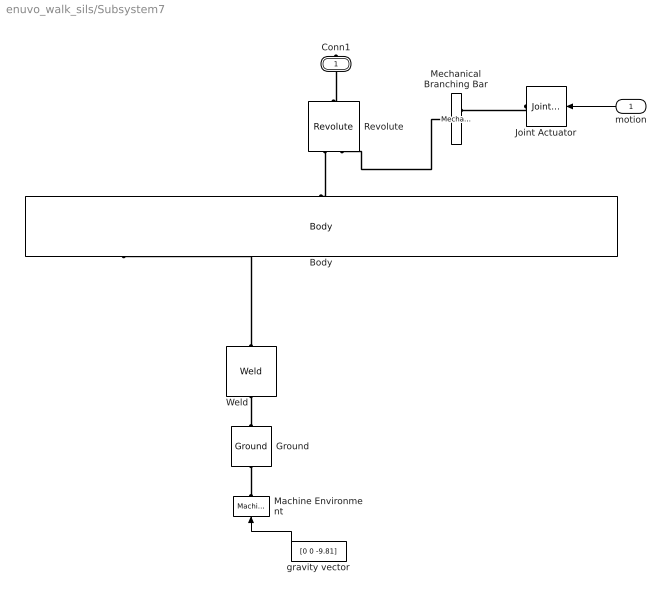
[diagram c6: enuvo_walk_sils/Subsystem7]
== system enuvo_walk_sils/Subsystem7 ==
  motion : Inport
  Body : mblibv1/Bodies/Body  LConnTagsString=CS1|CS3|CS4|CS5|CS6  RConnTagsString=CS2  UpdateFromCAD=off  DialogClass=MechanicalBodyBlock  Mass=8.7718241e-2  MassUnits=kg  InertiaUnits=kg*m^2  Inertia=1e-3*diag([4.5614162e-2 6.5533040e-2 5.6545514e-2])  Shape=Cylinder  ShapeDims=[1 1]  ShapeUnits=m  ShapeUse=false  Density=1  DensityUnits=kg/m^3  DensityUse=false  GraphicsMode=MACHINE_DEFAULT  BodyColorSelMode=MACHINE_DEFAULT  BodyColor=[1;0;0]  AttachedToCS=CG  CG=Left$CG$[7.96 5.62 -13.41]$CS1$CS1$mm$[0 0 0]$Euler X-Y-Z$deg$WORLD$false  WorkingFrames=Left$CS1$[0 20 40]$WORLD$WORLD$mm$[0 0 0]$Euler X-Y-Z$deg$WORLD$true#Right$CS2$[0 0 0]$CS1$CS1$mm$[0 0 0]$Euler X-Y-Z$deg$WORLD$true#Left$CS3$[65 -12.5 -40]$CS1$CS1$mm$[0 0 0]$Euler X-Y-Z$deg$WORLD$true#Left$CS4$[-30 -12.5 -40]$CS1$CS1$mm$[0 0 0]$Euler X-Y-Z$deg$WORLD$true#Left$CS5$[65 42.5 -40]$CS1$CS1$mm$[0 0 0]$Euler X-Y-Z$deg$WORLD$true#Left$CS6$[-30 42.5 -40]$CS1$CS1$mm$[0 0 0]$Euler X-Y-Z$de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  CGPos=[7.96 5.62 -13.41]  CGRot=[0 0 0]  CS0Pos=[]  CS0Rot=[]  CS1Pos=[0 20 40]  CS1Rot=[0 0 0]  CS2Pos=[0 0 0]  CS2Rot=[0 0 0]  CS3Pos=[65 -12.5 -40]  CS3Rot=[0 0 0]  CS4Pos=[-30 -12.5 -40]  CS4Rot=[0 0 0]  CS5Pos=[65 42.5 -40]  CS5Rot=[0 0 0]  CS6Pos=[-30 42.5 -40]  CS6Rot=[0 0 0]  CS7Pos=[]  CS7Rot=[]  CS8Pos=[]  CS8Rot=[]  CS9Pos=[]  CS9Rot=[]  CS10Pos=[]  CS10Rot=[]  CS11Pos=[]  CS11Rot=[]  CS12Pos=[]  CS12Rot=[]  CS13Pos=[]  CS13Rot=[]  CS14Pos=[]  CS14Rot=[]  CS15Pos=[]  CS15Rot=[]  CS16Pos=[]  CS16Rot=[]  CS17Pos=[]  CS17Rot=[]  CS18Pos=[]  CS18Rot=[]  CS19Pos=[]  CS19Rot=[]  CS20Pos=[]  CS20Rot=[]
  Ground : mblibv1/Bodies/Ground  UpdateFromCAD=off  LeftPortType=env  RightPortType=workingframe  PhysicalDomain=Mechanical  DialogClass=GroundBlock  CoordPosition=[0 20 40]  CoordPositionUnits=mm  StateVectorMgrId=0  MachineId=[1 0]  ShowEnvPort=on  ParameterChecksum=[128095518, 2569424456, 1912106411, 3626419035]  TopologyChecksum=[35605126, 1190613097, 3158114297, 2980425774]
  Joint Actuator : mblibv1/Sensors &  Actuators/Joint Actuator  UpdateFromCAD=off  PhysicalDomain=Mechanical  PortType=blob  ActuationStyle=Motion  AngleUnits=deg  ArcVelocityUnits=deg/s  ArcAccelerationUnits=deg/s^2  CoordPositionUnits=m  VelocityUnits=m/s  AccelerationUnits=m/s^2  ForceUnits=N  TorqueUnits=N-m  ActiveIO=on  Width=3  DialogClass=MechanicalActuatorBlock  Primitive=R1  ReferenceFrame=Absolute (INERTIAL)
  Machine Environment : mblibv1/Bodies/Machine Environment  Tag=Factory ground  PortType=env  PhysicalDomain=Mechanical  DialogTemplateClass=MECH.MachineEnvironment  SyncWhenCopied=off  Gravity=[0 0 9.81]  GravityUnits=m/s^2  GravityAsSignal=on  Dimensionality=Auto-detect  AnalysisType=Forward dynamics  LinearAssemblyTolerance=1e-3  LinearAssemblyToleranceUnits=m  AngularAssemblyTolerance=1e-3  AngularAssemblyToleranceUnits=rad  ConstraintSolverType=Machine precision  ConstraintRelTolerance=1e-4  ConstraintAbsTolerance=1e-4  UseRobustSingularityHandling=off  RedundancyAnalysisToleranceType=Automatically select tolerance  RedundancyAnalysisTolerance=1e-14  StatePerturbationType=Fixed  PerturbationSize=1e-5  VisualizeMachine=on  BodyVisualizationType=Use model default body geometries  BodyColorSelMode=Use model default  DefaultBodyColor=[1 0 0]
  Mechanical Branching Bar : mblibv1/Utilities/Mechanical Branching Bar  LConnTagsString=_newl0  RConnTagsString=SA0|SA1  UpdateFromCAD=off  DialogClass=MechanicalBranchingBarBlock  NumSAPorts=2
  Revolute : mblibv1/Joints/Revolute  LConnTagsString=__newl0|SA1  RConnTagsString=__newr0  UpdateFromCAD=off  NumSAPorts=1  CutJoint=off  MarkAsCut=off  Primitives=revolute  PrimitiveProps=R1$WORLD$[1 0 0]$revolute  DialogClass=JointBlock  R1Axis=[1 0 0]
  Weld : mblibv1/Joints/Weld  LConnTagsString=__newl0  RConnTagsString=__newr0  UpdateFromCAD=off  NumSAPorts=0  CutJoint=off  MarkAsCut=off  Primitives=weld  PrimitiveProps=W$WORLD$[0 0 0]$weld  DialogClass=JointBlock  WAxis=[0 0 0]
  gravity vector : Constant  Value=[0 0 -9.81]
  Conn1 : PMIOPort  Port=1  Side=Right
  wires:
  motion/1 -> Joint Actuator/1
  gravity vector/1 -> Machine Environment/1
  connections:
  Conn1/RConn1 -- Revolute/RConn1
  Mechanical Branching Bar/LConn1 -- Revolute/LConn2
  Joint Actuator/RConn1 -- Mechanical Branching Bar/RConn1
  Revolute/LConn1 -- Body/RConn1
  Machine Environment/RConn1 -- Ground/LConn1
  Weld/LConn1 -- Ground/RConn1
  Weld/RConn1 -- Body/LConn1

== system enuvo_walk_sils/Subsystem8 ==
  motion : Inport
  Body1 : mblibv1/Bodies/Body  LConnTagsString=CS1  RConnTagsString=CS2  UpdateFromCAD=off  DialogClass=MechanicalBodyBlock  Mass=1.7789708e-2  MassUnits=kg  InertiaUnits=kg*m^2  Inertia=1e-3*diag([3.2759472e-3 3.3173450e-3 4.8377597e-3])  Shape=Cylinder  ShapeDims=[1 1]  ShapeUnits=m  ShapeUse=false  Density=1  DensityUnits=kg/m^3  DensityUse=false  GraphicsMode=MACHINE_DEFAULT  BodyColorSelMode=MACHINE_DEFAULT  BodyColor=[1;0;0]  AttachedToCS=CG  CG=Left$CG$[-6.4 13.1 0]$CS1$CS1$mm$[0 0 0]$Euler X-Y-Z$deg$WORLD$false  WorkingFrames=Left$CS1$[0 20 40]$WORLD$WORLD$mm$[0 0 0]$Euler X-Y-Z$deg$WORLD$true#Right$CS2$[0 0 0]$CS1$CS1$mm$[0 0 0]$Euler X-Y-Z$deg$WORLD$true  CGPos=[-6.4 13.1 0]  CGRot=[0 0 0]  CS0Pos=[]  CS0Rot=[]  CS1Pos=[0 20 40]  CS1Rot=[0 0 0]  CS2Pos=[0 0 0]  CS2Rot=[0 0 0]  CS3Pos=[]  CS3Rot=[]  CS4Pos=[]  CS4Rot=[]  CS5Pos=[]  CS5Rot=[]  CS6Pos=[]  CS6Rot=[]  CS7Pos=[]  CS7Rot=[]  CS8Pos=[]  CS8Rot=[]  CS9Pos=[]  CS9Rot=[]  CS10Pos=[]  CS10Rot=[]  CS11Pos=[]  CS11Rot=[]  CS12Pos=[]  CS12Rot=[]  CS13Pos=[]  CS13Rot=[]  CS14Pos=[]  CS14Rot=[]  CS15Pos=[]  CS15Rot=[]  CS16Pos=[]  CS16Rot=[]  CS17Pos=[]  CS17Rot=[]  CS18Pos=[]  CS18Rot=[]  CS19Pos=[]  CS19Rot=[]  CS20Pos=[]  CS20Rot=[]
  Joint Actuator : mblibv1/Sensors &  Actuators/Joint Actuator  UpdateFromCAD=off  PhysicalDomain=Mechanical  PortType=blob  ActuationStyle=Motion  AngleUnits=deg  ArcVelocityUnits=deg/s  ArcAccelerationUnits=deg/s^2  CoordPositionUnits=m  VelocityUnits=m/s  AccelerationUnits=m/s^2  ForceUnits=N  TorqueUnits=N-m  ActiveIO=on  Width=3  DialogClass=MechanicalActuatorBlock  Primitive=R1  ReferenceFrame=Absolute (INERTIAL)
  Mechanical Branching Bar : mblibv1/Utilities/Mechanical Branching Bar  LConnTagsString=_newl0  RConnTagsString=SA0|SA1  UpdateFromCAD=off  DialogClass=MechanicalBranchingBarBlock  NumSAPorts=2
  Revolute1 : mblibv1/Joints/Revolute  LConnTagsString=__newl0|SA1  RConnTagsString=__newr0  UpdateFromCAD=off  NumSAPorts=1  CutJoint=off  MarkAsCut=off  Primitives=revolute  PrimitiveProps=R1$WORLD$[0 -1 0]$revolute  DialogClass=JointBlock  R1Axis=[0 -1 0]
  Conn1 : PMIOPort  Port=1  Side=Right
  Conn2 : PMIOPort  Port=2  Side=Left
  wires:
  motion/1 -> Joint Actuator/1
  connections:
  Body1/LConn1 -- Conn2/RConn1
  Revolute1/LConn1 -- Body1/RConn1
  Revolute1/RConn1 -- Conn1/RConn1
  Joint Actuator/RConn1 -- Mechanical Branching Bar/RConn1
  Mechanical Branching Bar/LConn1 -- Revolute1/LConn2

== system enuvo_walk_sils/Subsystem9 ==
  motion : Inport
  Body2 : mblibv1/Bodies/Body  LConnTagsString=CS1  RConnTagsString=CS2  UpdateFromCAD=off  DialogClass=MechanicalBodyBlock  Mass=1.2799082e-1  MassUnits=kg  InertiaUnits=kg*m^2  Inertia=1e-3*diag([1.2927724e-1 9.7937726e-2 5.7245228e-2])  Shape=Cylinder  ShapeDims=[1 1]  ShapeUnits=m  ShapeUse=false  Density=1  DensityUnits=kg/m^3  DensityUse=false  GraphicsMode=MACHINE_DEFAULT  BodyColorSelMode=MACHINE_DEFAULT  BodyColor=[1;0;0]  AttachedToCS=CG  CG=Left$CG$[10.55 32.59 38.17]$CS1$CS1$mm$[0 0 0]$Euler X-Y-Z$deg$WORLD$false  WorkingFrames=Left$CS1$[0 20 40]$WORLD$WORLD$mm$[0 0 0]$Euler X-Y-Z$deg$WORLD$true#Right$CS2$[0 0 85]$CS1$CS1$mm$[0 0 0]$Euler X-Y-Z$deg$WORLD$true  CGPos=[10.55 32.59 38.17]  CGRot=[0 0 0]  CS0Pos=[]  CS0Rot=[]  CS1Pos=[0 20 40]  CS1Rot=[0 0 0]  CS2Pos=[0 0 85]  CS2Rot=[0 0 0]  CS3Pos=[]  CS3Rot=[]  CS4Pos=[]  CS4Rot=[]  CS5Pos=[]  CS5Rot=[]  CS6Pos=[]  CS6Rot=[]  CS7Pos=[]  CS7Rot=[]  CS8Pos=[]  CS8Rot=[]  CS9Pos=[]  CS9Rot=[]  CS10Pos=[]  CS10Rot=[]  CS11Pos=[]  CS11Rot=[]  CS12Pos=[]  CS12Rot=[]  CS13Pos=[]  CS13Rot=[]  CS14Pos=[]  CS14Rot=[]  CS15Pos=[]  CS15Rot=[]  CS16Pos=[]  CS16Rot=[]  CS17Pos=[]  CS17Rot=[]  CS18Pos=[]  CS18Rot=[]  CS19Pos=[]  CS19Rot=[]  CS20Pos=[]  CS20Rot=[]
  Joint Actuator : mblibv1/Sensors &  Actuators/Joint Actuator  UpdateFromCAD=off  PhysicalDomain=Mechanical  PortType=blob  ActuationStyle=Motion  AngleUnits=deg  ArcVelocityUnits=deg/s  ArcAccelerationUnits=deg/s^2  CoordPositionUnits=m  VelocityUnits=m/s  AccelerationUnits=m/s^2  ForceUnits=N  TorqueUnits=N-m  ActiveIO=on  Width=3  DialogClass=MechanicalActuatorBlock  Primitive=R1  ReferenceFrame=Absolute (INERTIAL)
  Mechanical Branching Bar : mblibv1/Utilities/Mechanical Branching Bar  LConnTagsString=_newl0  RConnTagsString=SA0|SA1  UpdateFromCAD=off  DialogClass=MechanicalBranchingBarBlock  NumSAPorts=2
  Revolute2 : mblibv1/Joints/Revolute  LConnTagsString=__newl0|SA1  RConnTagsString=__newr0  UpdateFromCAD=off  NumSAPorts=1  CutJoint=off  MarkAsCut=off  Primitives=revolute  PrimitiveProps=R1$WORLD$[0 -1 0]$revolute  DialogClass=JointBlock  R1Axis=[0 -1 0]
  Conn1 : PMIOPort  Port=1  Side=Right
  Conn2 : PMIOPort  Port=2  Side=Left
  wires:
  motion/1 -> Joint Actuator/1
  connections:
  Body2/LConn1 -- Conn2/RConn1
  Body2/RConn1 -- Revolute2/LConn1
  Revolute2/RConn1 -- Conn1/RConn1
  Joint Actuator/RConn1 -- Mechanical Branching Bar/RConn1
  Mechanical Branching Bar/LConn1 -- Revolute2/LConn2

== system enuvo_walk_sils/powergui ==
  note: Graphical user interface for the analysis of SimPowerSystems circuits. Place the Powergui block in the top-level of your model and double-click on it to open the GUI.
  EquivalentModel1 : Subsystem
  EquivalentModel2 : Subsystem
  Ground : Ground
  Terminator : Terminator
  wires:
  Ground/1 -> Terminator/1

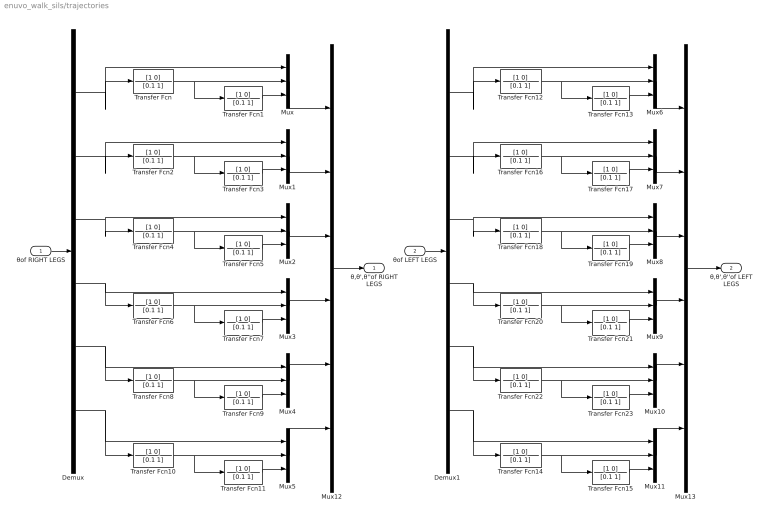
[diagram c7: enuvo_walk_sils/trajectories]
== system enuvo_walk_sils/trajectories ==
  θof RIGHT LEGS : Inport
  θof LEFT LEGS : Inport  Port=2
  Demux : Demux  Outputs=6
  Demux1 : Demux  Outputs=6
  Mux{,1..11} (12 alike) : Mux  Inputs=3
  Mux12 : Mux  Inputs=6
  Mux13 : Mux  Inputs=6
  Transfer Fcn{,1..23} (24 alike) : TransferFcn  Numerator=[1 0]  Denominator=[0.1 1]
  θ,θ',θ''of RIGHT LEGS : Outport
  θ,θ',θ''of LEFT LEGS : Outport  Port=2
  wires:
  Mux/1 -> Mux12/1
  Demux/1 -> Mux/1, Transfer Fcn/1
  Transfer Fcn/1 -> Mux/2, Transfer Fcn1/1
  Transfer Fcn1/1 -> Mux/3
  Demux/2 -> Transfer Fcn2/1, Mux1/1
  Transfer Fcn2/1 -> Transfer Fcn3/1, Mux1/2
  Transfer Fcn3/1 -> Mux1/3
  Demux/3 -> Mux2/1, Transfer Fcn4/1
  Transfer Fcn4/1 -> Mux2/2, Transfer Fcn5/1
  Transfer Fcn5/1 -> Mux2/3
  Demux/4 -> Transfer Fcn6/1, Mux3/1
  Transfer Fcn6/1 -> Transfer Fcn7/1, Mux3/2
  Transfer Fcn7/1 -> Mux3/3
  Demux/5 -> Mux4/1, Transfer Fcn8/1
  Transfer Fcn8/1 -> Mux4/2, Transfer Fcn9/1
  Transfer Fcn9/1 -> Mux4/3
  Demux/6 -> Transfer Fcn10/1, Mux5/1
  Transfer Fcn10/1 -> Transfer Fcn11/1, Mux5/2
  Transfer Fcn11/1 -> Mux5/3
  Demux1/1 -> Transfer Fcn12/1, Mux6/1
  Transfer Fcn12/1 -> Transfer Fcn13/1, Mux6/2
  Transfer Fcn13/1 -> Mux6/3
  Demux1/2 -> Mux7/1, Transfer Fcn16/1
  Transfer Fcn16/1 -> Mux7/2, Transfer Fcn17/1
  Transfer Fcn17/1 -> Mux7/3
  Demux1/3 -> Transfer Fcn18/1, Mux8/1
  Transfer Fcn18/1 -> Transfer Fcn19/1, Mux8/2
  Transfer Fcn19/1 -> Mux8/3
  Demux1/4 -> Mux9/1, Transfer Fcn20/1
  Transfer Fcn20/1 -> Mux9/2, Transfer Fcn21/1
  Transfer Fcn21/1 -> Mux9/3
  Demux1/5 -> Transfer Fcn22/1, Mux10/1
  Transfer Fcn22/1 -> Transfer Fcn23/1, Mux10/2
  Transfer Fcn23/1 -> Mux10/3
  Demux1/6 -> Mux11/1, Transfer Fcn14/1
  Transfer Fcn14/1 -> Mux11/2, Transfer Fcn15/1
  Transfer Fcn15/1 -> Mux11/3
  Mux1/1 -> Mux12/2
  Mux2/1 -> Mux12/3
  Mux3/1 -> Mux12/4
  Mux4/1 -> Mux12/5
  Mux5/1 -> Mux12/6
  Mux6/1 -> Mux13/1
  Mux7/1 -> Mux13/2
  Mux8/1 -> Mux13/3
  Mux9/1 -> Mux13/4
  Mux10/1 -> Mux13/5
  Mux11/1 -> Mux13/6
  θof RIGHT LEGS/1 -> Demux/1
  θof LEFT LEGS/1 -> Demux1/1
  Mux12/1 -> θ,θ',θ''of RIGHT LEGS/1
  Mux13/1 -> θ,θ',θ''of LEFT LEGS/1

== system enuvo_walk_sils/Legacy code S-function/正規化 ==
  note: 符号ビット1+10ビットで 表現できる最大数
  note: PID制御器の出力 最大2047最小-2047
  note: PID制御器の出力を補正して最大1最小-1（double）とする。
  In1 : Inport
  Data Type Conversion2 : DataTypeConversion  OutDataTypeStr=double
  Gain : Gain
  Gain1 : Gain  Gain=1/2047
  Out1 : Outport
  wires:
  In1/1 -> Gain/1
  Gain/1 -> Data Type Conversion2/1
  Gain1/1 -> Out1/1
  Data Type Conversion2/1 -> Gain1/1

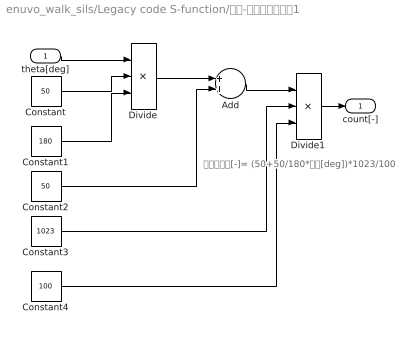
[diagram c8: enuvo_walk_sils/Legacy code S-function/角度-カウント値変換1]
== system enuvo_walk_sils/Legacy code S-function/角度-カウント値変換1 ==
  note: カウント値[-]= (50+50/180*角度[deg])*1023/100
  theta[deg] : Inport
  Add : Sum
  Constant : Constant  Value=50
  Constant1 : Constant  Value=180
  Constant2 : Constant  Value=50
  Constant3 : Constant  Value=1023
  Constant4 : Constant  Value=100
  Divide : Product  Inputs=**/
  Divide1 : Product  Inputs=**/
  count[-] : Outport
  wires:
  Constant/1 -> Divide/2
  Constant1/1 -> Divide/3
  Divide/1 -> Add/1
  Constant2/1 -> Add/2
  Add/1 -> Divide1/1
  Constant3/1 -> Divide1/2
  Constant4/1 -> Divide1/3
  theta[deg]/1 -> Divide/1
  Divide1/1 -> count[-]/1

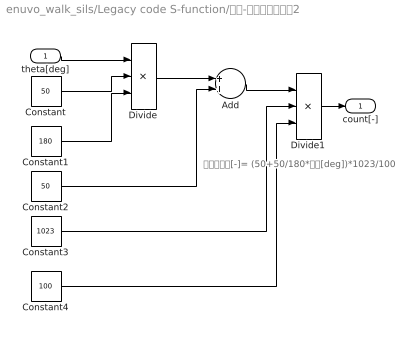
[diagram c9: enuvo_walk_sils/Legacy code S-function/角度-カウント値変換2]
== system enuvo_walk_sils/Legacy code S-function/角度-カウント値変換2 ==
  note: カウント値[-]= (50+50/180*角度[deg])*1023/100
  theta[deg] : Inport
  Add : Sum
  Constant : Constant  Value=50
  Constant1 : Constant  Value=180
  Constant2 : Constant  Value=50
  Constant3 : Constant  Value=1023
  Constant4 : Constant  Value=100
  Divide : Product  Inputs=**/
  Divide1 : Product  Inputs=**/
  count[-] : Outport
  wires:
  Divide1/1 -> count[-]/1
  theta[deg]/1 -> Divide/1
  Constant4/1 -> Divide1/3
  Constant3/1 -> Divide1/2
  Add/1 -> Divide1/1
  Constant2/1 -> Add/2
  Divide/1 -> Add/1
  Constant1/1 -> Divide/3
  Constant/1 -> Divide/2
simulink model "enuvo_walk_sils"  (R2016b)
settings: Solver=ode23tb  StartTime=0.0  StopTime=LAST_TIME  FixedStep=0.01  EnableMultiTasking=on
PreLoadFcn:
  | load('PID_PARAMETER');
  | N=40;
  | eta=1;
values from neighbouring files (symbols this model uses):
  A = [1 0 0 0 0 0    [symbolic_sample.m]
  s = robot_para.s    [kinematics_calc.m]    (also in plot_graph.m; robot_parameter.m = 40; robot_view.m)
undefined symbols (not defined in the file or in its folder): arm, bridge, constant, deg, kg, m, powergui, pulses, rad, S, Torque
libraries: mblibv1 x53, powerlib x7, powerlib_extras x1
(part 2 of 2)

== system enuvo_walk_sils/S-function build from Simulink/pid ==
  ref : Inport  OutDataTypeStr=uint16
  pos : Inport  Port=2  OutDataTypeStr=uint16
  __InputSSForSFun__ : Subsystem
  __OutputSSForSFun__ : Subsystem
  pid_sfcn : S-Function  FunctionName=pid0_sf  SFunctionModules=""  SFunctionDeploymentMode=off  EnableBusSupport=off  SFcnStateName=DWORK0
  out : Outport  OutDataTypeStr=int16
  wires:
  ref/1 -> __InputSSForSFun__/1(ref)
  pos/1 -> __InputSSForSFun__/2(pos)
  __InputSSForSFun__/1(__UniqueOutportName__1__) -> pid_sfcn/1
  __InputSSForSFun__/2(__UniqueOutportName__2__) -> pid_sfcn/2
  pid_sfcn/1 -> __OutputSSForSFun__/1(__UniqueInportName__1__)
  __OutputSSForSFun__/1(out) -> out/1

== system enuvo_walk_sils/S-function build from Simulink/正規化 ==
  note: PID制御器の出力を補正して最大1最小-1（double）とする。
  note: PID制御器の出力 最大2047最小-2047
  note: 符号ビット1+10ビットで 表現できる最大数
  In1 : Inport
  Data Type Conversion2 : DataTypeConversion  OutDataTypeStr=double
  Gain : Gain
  Gain1 : Gain  Gain=1/2047
  Out1 : Outport
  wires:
  Data Type Conversion2/1 -> Gain1/1
  Gain1/1 -> Out1/1
  Gain/1 -> Data Type Conversion2/1
  In1/1 -> Gain/1

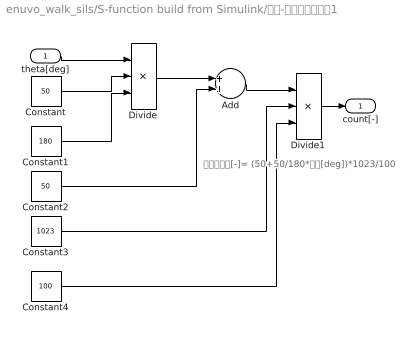
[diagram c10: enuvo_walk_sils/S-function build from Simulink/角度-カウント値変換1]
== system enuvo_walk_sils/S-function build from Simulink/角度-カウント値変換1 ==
  note: カウント値[-]= (50+50/180*角度[deg])*1023/100
  theta[deg] : Inport
  Add : Sum
  Constant : Constant  Value=50
  Constant1 : Constant  Value=180
  Constant2 : Constant  Value=50
  Constant3 : Constant  Value=1023
  Constant4 : Constant  Value=100
  Divide : Product  Inputs=**/
  Divide1 : Product  Inputs=**/
  count[-] : Outport
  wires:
  Divide1/1 -> count[-]/1
  theta[deg]/1 -> Divide/1
  Constant4/1 -> Divide1/3
  Constant3/1 -> Divide1/2
  Add/1 -> Divide1/1
  Constant2/1 -> Add/2
  Divide/1 -> Add/1
  Constant1/1 -> Divide/3
  Constant/1 -> Divide/2

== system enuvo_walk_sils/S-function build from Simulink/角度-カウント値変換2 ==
  note: カウント値[-]= (50+50/180*角度[deg])*1023/100
  theta[deg] : Inport
  Add : Sum
  Constant : Constant  Value=50
  Constant1 : Constant  Value=180
  Constant2 : Constant  Value=50
  Constant3 : Constant  Value=1023
  Constant4 : Constant  Value=100
  Divide : Product  Inputs=**/
  Divide1 : Product  Inputs=**/
  count[-] : Outport
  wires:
  Constant/1 -> Divide/2
  Constant1/1 -> Divide/3
  Divide/1 -> Add/1
  Constant2/1 -> Add/2
  Add/1 -> Divide1/1
  Constant3/1 -> Divide1/2
  Constant4/1 -> Divide1/3
  theta[deg]/1 -> Divide/1
  Divide1/1 -> count[-]/1

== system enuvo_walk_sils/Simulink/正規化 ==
  note: PID制御器の出力を補正して最大1最小-1（double）とする。
  note: PID制御器の出力 最大2047最小-2047
  note: 符号ビット1+10ビットで 表現できる最大数
  In1 : Inport
  Data Type Conversion2 : DataTypeConversion  OutDataTypeStr=double
  Gain : Gain
  Gain1 : Gain  Gain=1/2047
  Out1 : Outport
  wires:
  Data Type Conversion2/1 -> Gain1/1
  Gain1/1 -> Out1/1
  Gain/1 -> Data Type Conversion2/1
  In1/1 -> Gain/1

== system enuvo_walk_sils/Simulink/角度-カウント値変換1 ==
  note: カウント値[-]= (50+50/180*角度[deg])*1023/100
  theta[deg] : Inport
  Add : Sum
  Constant : Constant  Value=50
  Constant1 : Constant  Value=180
  Constant2 : Constant  Value=50
  Constant3 : Constant  Value=1023
  Constant4 : Constant  Value=100
  Divide : Product  Inputs=**/
  Divide1 : Product  Inputs=**/
  count[-] : Outport
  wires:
  Divide1/1 -> count[-]/1
  theta[deg]/1 -> Divide/1
  Constant4/1 -> Divide1/3
  Constant3/1 -> Divide1/2
  Add/1 -> Divide1/1
  Constant2/1 -> Add/2
  Divide/1 -> Add/1
  Constant1/1 -> Divide/3
  Constant/1 -> Divide/2

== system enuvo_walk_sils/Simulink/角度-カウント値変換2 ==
  note: カウント値[-]= (50+50/180*角度[deg])*1023/100
  theta[deg] : Inport
  Add : Sum
  Constant : Constant  Value=50
  Constant1 : Constant  Value=180
  Constant2 : Constant  Value=50
  Constant3 : Constant  Value=1023
  Constant4 : Constant  Value=100
  Divide : Product  Inputs=**/
  Divide1 : Product  Inputs=**/
  count[-] : Outport
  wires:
  Constant/1 -> Divide/2
  Constant1/1 -> Divide/3
  Divide/1 -> Add/1
  Constant2/1 -> Add/2
  Add/1 -> Divide1/1
  Constant3/1 -> Divide1/2
  Constant4/1 -> Divide1/3
  theta[deg]/1 -> Divide/1
  Divide1/1 -> count[-]/1

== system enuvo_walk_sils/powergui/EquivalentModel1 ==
  Sources : Subsystem
  State-Space : StateSpace  A=S.A  B=S.B  C=S.C  D=S.D  X0=S.x0
  Yout : Subsystem
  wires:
  Sources/1(u) -> State-Space/1
  State-Space/1 -> Yout/1(v,i)

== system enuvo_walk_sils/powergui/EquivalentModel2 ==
  Gates : Subsystem
  Sources : Subsystem
  State-Space : S-Function  FunctionName=sfun_spssw_contc  Parameters=S.A, S.B, S.C, S.D, S.x0, S.EnableUseOfTLC,S.SwitchResistance ,S.SwitchType, S.SwitchGateInitialValue, S.OutputsToResetToZero,S.SaveMatrices,S.BufferSize  SFunctionDeploymentMode=off  EnableBusSupport=off
  Status : Subsystem
  Yout : Subsystem
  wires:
  Gates/1(gates) -> State-Space/2
  Sources/1(u) -> State-Space/1
  State-Space/2 -> Status/1(status)
  State-Space/1 -> Yout/1(v,i)

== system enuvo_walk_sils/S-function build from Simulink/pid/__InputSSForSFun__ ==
  ref : Inport  OutDataTypeStr=uint16
  pos : Inport  Port=2  OutDataTypeStr=uint16
  __UniqueOutportName__1__ : Outport
  __UniqueOutportName__2__ : Outport  Port=2
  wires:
  ref/1 -> __UniqueOutportName__1__/1
  pos/1 -> __UniqueOutportName__2__/1

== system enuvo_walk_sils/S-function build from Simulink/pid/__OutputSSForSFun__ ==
  __UniqueInportName__1__ : Inport
  out : Outport  OutDataTypeStr=int16
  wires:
  __UniqueInportName__1__/1 -> out/1  "result2"

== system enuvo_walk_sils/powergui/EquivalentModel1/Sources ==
  Mux : Mux  Inputs=1
  u : Outport
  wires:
  Mux/1 -> u/1
  [T55_4923_4737468266579] -> Mux/1

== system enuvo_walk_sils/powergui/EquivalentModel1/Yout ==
  v,i : Inport
  Demux : Demux  Outputs=1
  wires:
  v,i/1 -> Demux/1
  Demux/1 -> [T45_4132_3280055942343]

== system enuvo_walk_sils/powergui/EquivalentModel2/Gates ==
  Mux : Mux  Inputs=[1 1 1 1 1 1 1 1]
  gates : Outport
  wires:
  Mux/1 -> gates/1
  [T50_4659_4067147017588] -> Mux/1
  [T50_4658_4068672412016] -> Mux/2
  [T50_4657_4070266034045] -> Mux/3
  [T49_4608_3928406359787] -> Mux/4
  [T42_3956_2752914347997] -> Mux/5
  [T43_4005_2830964053455] -> Mux/6
  [T43_4006_2829973740742] -> Mux/7
  [T43_4007_2829062762447] -> Mux/8

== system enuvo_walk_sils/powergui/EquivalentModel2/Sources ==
  Mux : Mux  Inputs=[1 1]
  Mux_u : Mux  Inputs=[8 2]
  SwitchCurrents : Constant  Value=zeros(8,1)
  u : Outport
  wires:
  Mux/1 -> Mux_u/2
  SwitchCurrents/1 -> Mux_u/1
  Mux_u/1 -> u/1
  [T47_4348_3680496941628] -> Mux/1
  [T45_3992_2641319216545] -> Mux/2

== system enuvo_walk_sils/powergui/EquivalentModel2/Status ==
  status : Inport
  Demux : Demux  Outputs=[1 1 1 1 1 1 1 1]
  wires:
  status/1 -> Demux/1
  Demux/1 -> [T52_4894_4728948527994]
  Demux/2 -> [T52_4893_4730714335034]
  Demux/3 -> [T52_4892_4732545745535]
  Demux/4 -> [T51_4843_4563935834196]
  Demux/5 -> [T44_4191_3310539437653]
  Demux/6 -> [T45_4240_3419252944545]
  Demux/7 -> [T45_4241_3417957797404]
  Demux/8 -> [T45_4242_3416738458707]

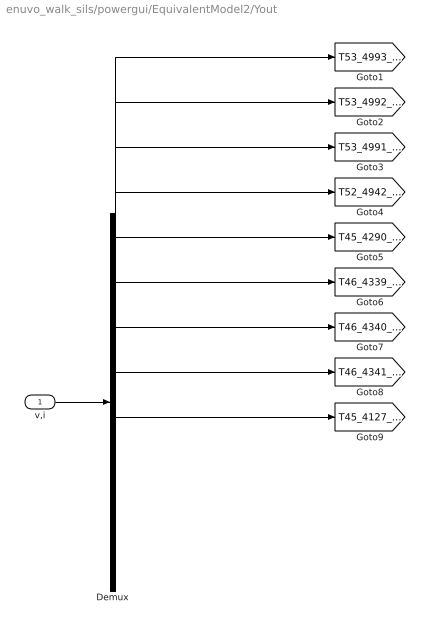
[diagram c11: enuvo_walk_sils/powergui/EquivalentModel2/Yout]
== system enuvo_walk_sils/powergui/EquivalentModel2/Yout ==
  v,i : Inport
  Demux : Demux  Outputs=[1 1 1 1 1 1 1 1 1]
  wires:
  v,i/1 -> Demux/1
  Demux/1 -> [T53_4993_4844208824064]
  Demux/2 -> [T53_4992_4846047318440]
  Demux/3 -> [T53_4991_4847950178476]
  Demux/4 -> [T52_4942_4671894134913]
  Demux/5 -> [T45_4290_3404636063636]
  Demux/6 -> [T46_4339_3522271260720]
  Demux/7 -> [T46_4340_3520881232406]
  Demux/8 -> [T46_4341_3519565364527]
  Demux/9 -> [T45_4127_3272574292646]
